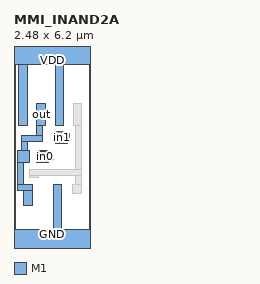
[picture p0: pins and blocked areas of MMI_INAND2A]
MACRO MMI_INAND2A
	CLASS CORE ;
	FOREIGN MMI_INAND2A 0 0 ;
	SIZE 2.48 BY 6.2 ;
	SYMMETRY X Y ;
	SITE CORE1 ;
	PIN out
		DIRECTION output ;
		USE SIGNAL ;
		PORT
			LAYER M1 ;
			RECT 0.75 3.815 1.03 4.515 ;
			LAYER M1 ;
			RECT 0.75 3.465 0.94 3.815 ;
			LAYER M1 ;
			RECT 0.245 3.27 0.94 3.465 ;
			LAYER M1 ;
			RECT 0.245 2.98 0.435 3.27 ;
			LAYER M1 ;
			RECT 0.12 2.58 0.5 2.98 ;
			LAYER M1 ;
			RECT 0.12 1.89 0.315 2.58 ;
			LAYER M1 ;
			RECT 0.12 1.885 0.59 1.89 ;
			LAYER M1 ;
			RECT 0.12 1.695 0.595 1.885 ;
			LAYER M1 ;
			RECT 0.315 1.185 0.595 1.695 ;
		END
		AntennaDiffArea 0.64295 ;
	END out
	PIN in1
		DIRECTION input ;
		USE SIGNAL ;
		PORT
			LAYER M1 ;
			RECT 1.36 3.54 1.74 3.6 ;
			LAYER M1 ;
			RECT 1.36 3.26 1.8 3.54 ;
			LAYER M1 ;
			RECT 1.36 3.22 1.74 3.26 ;
		END
		AntennaGateArea 0.17325 ;
	END in1
	PIN GND
		DIRECTION inout ;
		USE GROUND ;
		PORT
			LAYER M1 ;
			RECT 1.28 0.42 1.56 1.885 ;
			LAYER M1 ;
			RECT 0 -0.42 2.48 0.42 ;
		END
	END GND
	PIN VDD
		DIRECTION inout ;
		USE POWER ;
		PORT
			LAYER M1 ;
			RECT 0 5.78 2.48 6.62 ;
			LAYER M1 ;
			RECT 0.16 3.815 0.44 5.78 ;
			LAYER M1 ;
			RECT 1.34 3.815 1.62 5.78 ;
		END
	END VDD
	PIN in0
		DIRECTION input ;
		USE SIGNAL ;
		PORT
			LAYER M1 ;
			RECT 0.74 2.945 1.12 2.98 ;
			LAYER M1 ;
			RECT 0.74 2.885 1.24 2.945 ;
			LAYER M1 ;
			RECT 0.74 2.695 1.295 2.885 ;
			LAYER M1 ;
			RECT 0.74 2.665 1.24 2.695 ;
			LAYER M1 ;
			RECT 0.74 2.6 1.12 2.665 ;
		END
		AntennaGateArea 0.231 ;
	END in0
	OBS
		LAYER M1 ;
		RECT 1.93 3.815 2.21 4.515 ;
		LAYER M1 ;
		RECT 2.005 2.37 2.195 3.815 ;
		LAYER M1 ;
		RECT 0.515 2.18 2.195 2.37 ;
		LAYER M1 ;
		RECT 0.515 2.09 0.795 2.18 ;
		LAYER M1 ;
		RECT 2.005 1.89 2.195 2.18 ;
		LAYER M1 ;
		RECT 1.915 1.575 2.195 1.89 ;
	END
END MMI_INAND2A
